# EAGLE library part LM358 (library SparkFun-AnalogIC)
Jellybean op-amp

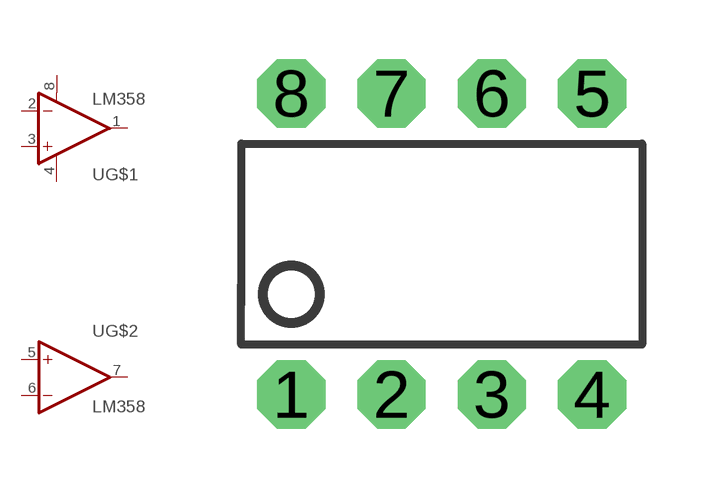
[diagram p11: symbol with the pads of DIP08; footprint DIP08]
Designator prefix -; gates G$1=OP-AMP+- G$2=OP-AMP

## LM358  [DIP08]
1  G$1:OUT  out
2  G$1:-IN  in
3  G$1:+IN  in
4  G$1:V-  pwr
5  G$2:+IN  in
6  G$2:-IN  in
7  G$2:OUT  out
8  G$1:V+  pwr

## Footprint DIP08 (pad centres in mm)
Dual In Line
drill 0.813 pad 1.727 octagon: 1 -3.81,-3.81; 2 -1.27,-3.81; 3 1.27,-3.81; 4 3.81,-3.81; 5 3.81,3.81; 6 1.27,3.81; 7 -1.27,3.81; 8 -3.81,3.81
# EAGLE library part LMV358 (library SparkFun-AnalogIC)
Jellybean rail-to-rail output op-amp

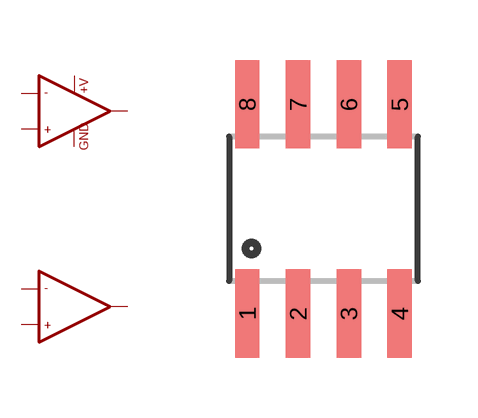
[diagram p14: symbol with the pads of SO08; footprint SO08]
Designator prefix -; gates G$1=OPAMP_2 G$2=OPAMP_2_1

## LMV358 (PROD_ID: IC-09657)  [SO08]
1  G$1:OUT1  out
2  G$1:-IN1  in
3  G$1:+IN1  in
4  G$1:GND  pwr
5  G$2:+IN2  in
6  G$2:-IN2  in
7  G$2:OUT2  out
8  G$1:+V  pwr

## Footprint SO08 (pad centres in mm)
Small Outline Package Fits JEDEC packages (narrow SOIC-8)
smd 0.61 x 2.21: 1 -1.905,-2.616; 2 -0.635,-2.616; 3 0.635,-2.616; 4 1.905,-2.616; 5 1.905,2.616; 6 0.635,2.616; 7 -0.635,2.616; 8 -1.905,2.616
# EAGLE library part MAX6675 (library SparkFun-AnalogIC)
K-type thermocouple ADC, SPI output

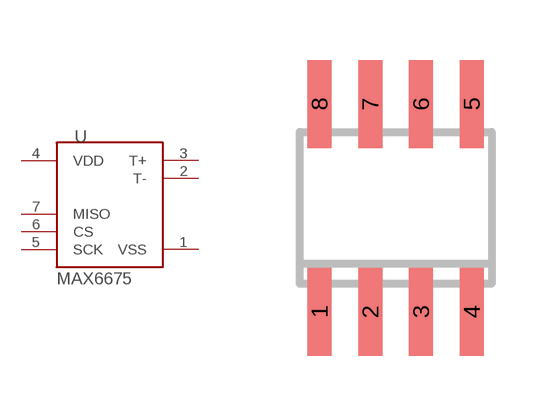
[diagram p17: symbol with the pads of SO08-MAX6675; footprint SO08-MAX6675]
Designator prefix -

## MAX6675  [SO08-MAX6675]
1  VSS
2  T-
3  T+
4  VDD
5  SCK
6  CS
7  MISO

## Footprint SO08-MAX6675 (pad centres in mm)
SMALL OUTLINE INTEGRATED CIRCUIT body 3.9 mm/JEDEC MS-012AA
smd 0.6 x 2.2: 1 -1.905,-2.6; 2 -0.635,-2.6; 3 0.635,-2.6; 4 1.905,-2.6; 5 1.905,2.6; 6 0.635,2.6; 7 -0.635,2.6; 8 -1.905,2.6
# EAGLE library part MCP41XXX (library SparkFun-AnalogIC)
SPI controlled single digital potentiometer by Microchip

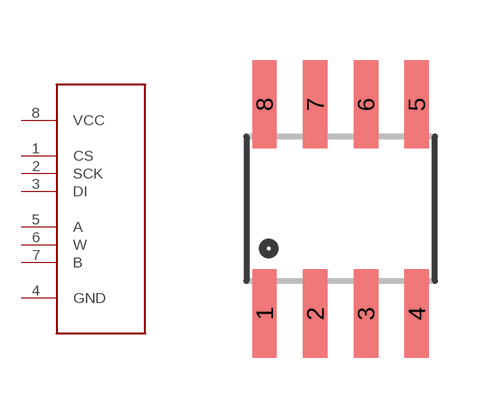
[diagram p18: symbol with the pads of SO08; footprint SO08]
Designator prefix U

## MCP41XXX  [SO08]
1  CS
2  SCK
3  DI
4  GND
5  A
6  W
7  B
8  VCC

## Footprint SO08 (pad centres in mm)
Small Outline Package Fits JEDEC packages (narrow SOIC-8)
smd 0.61 x 2.21: 1 -1.905,-2.616; 2 -0.635,-2.616; 3 0.635,-2.616; 4 1.905,-2.616; 5 1.905,2.616; 6 0.635,2.616; 7 -0.635,2.616; 8 -1.905,2.616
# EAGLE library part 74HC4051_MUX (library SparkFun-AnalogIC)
8:1 analog mux

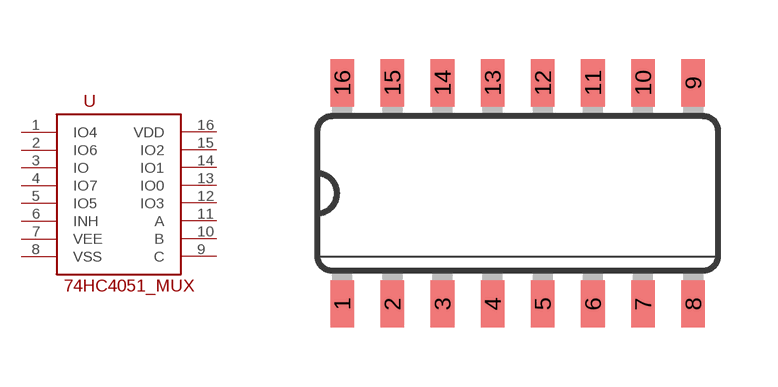
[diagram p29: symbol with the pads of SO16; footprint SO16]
Designator prefix -

## 74HC4051_MUX  [SO16]
1  IO4
2  IO6
3  IO
4  IO7
5  IO5
6  INH
7  VEE
8  VSS
9  C
10  B
11  A
12  IO3
13  IO0
14  IO1
15  IO2
16  VDD

## Footprint SO16 (pad centres in mm)
Small Outline package 150 mil
smd 0.6 x 1.2: 1 -4.445,-2.8; 2 -3.175,-2.8; 3 -1.905,-2.8; 4 -0.635,-2.8; 5 0.635,-2.8; 6 1.905,-2.8; 7 3.175,-2.8; 8 4.445,-2.8; 9 4.445,2.8; 10 3.175,2.8; 11 1.905,2.8; 12 0.635,2.8; 13 -0.635,2.8; 14 -1.905,2.8; 15 -3.175,2.8; 16 -4.445,2.8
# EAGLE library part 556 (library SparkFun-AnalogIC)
Dual timer circuit (2 555 timers in one package)

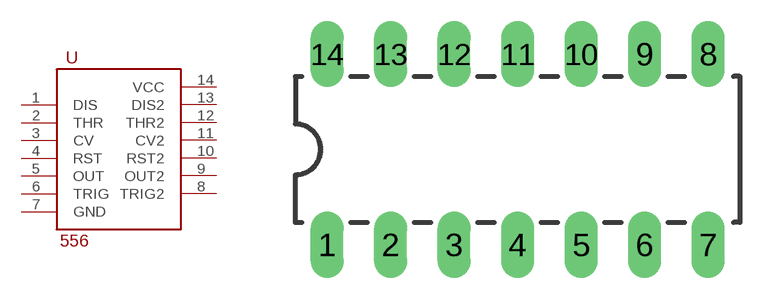
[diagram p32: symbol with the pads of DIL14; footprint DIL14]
Designator prefix -

## 556  [DIL14]
1  DIS
2  THR
3  CV
4  RST
5  OUT
6  TRIG
7  GND
8  TRIG2
9  OUT2
10  RST2
11  CV2
12  THR2
13  DIS2
14  VCC

## Footprint DIL14 (pad centres in mm)
drill 0.813 long: 1 -8.89,-3.81; 2 -6.35,-3.81; 3 -3.81,-3.81; 4 -1.27,-3.81; 5 1.27,-3.81; 6 3.81,-3.81; 7 6.35,-3.81; 8 6.35,3.81; 9 3.81,3.81; 10 1.27,3.81; 11 -1.27,3.81; 12 -3.81,3.81; 13 -6.35,3.81; 14 -8.89,3.81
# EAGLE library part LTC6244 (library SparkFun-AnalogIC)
Low-noise, high-speed rail-to-rail CMOS op-amp

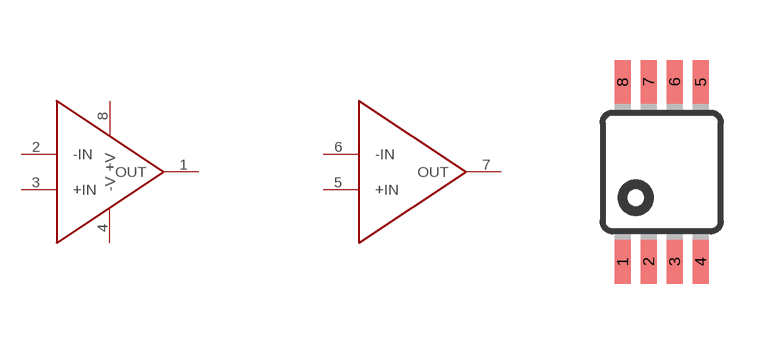
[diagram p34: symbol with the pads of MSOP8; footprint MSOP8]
Designator prefix -; gates G$1=LTC6244 G$2=LTC6244_2

## LTC6244  [MSOP8]
1  G$1:OUT
2  G$1:-IN
3  G$1:+IN
4  G$1:-V
5  G$2:+IN
6  G$2:-IN
7  G$2:OUT
8  G$1:+V

## Footprint MSOP8 (pad centres in mm)
8M, 8-Lead, 0.118" Wide, Miniature Small Outline Package MSOP 8M-Package doc1097.pdf
smd 0.4 x 1.1: 1 -0.975,-2.25; 2 -0.325,-2.25; 3 0.325,-2.25; 4 0.975,-2.25; 5 0.975,2.25; 6 0.325,2.25; 7 -0.325,2.25; 8 -0.975,2.25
